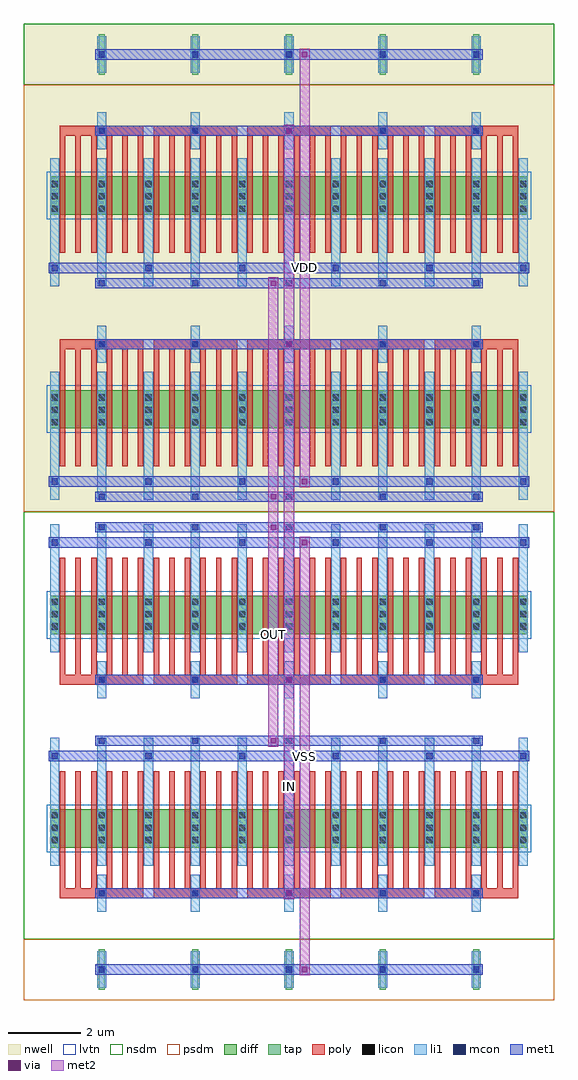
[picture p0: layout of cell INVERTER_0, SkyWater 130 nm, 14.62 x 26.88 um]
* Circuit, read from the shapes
.subckt INVERTER_0 IN OUT VDD VSS
XM1 n1 IN VSS VSS sky130_fd_pr__nfet_01v8_lvt w=1.05 l=0.15
XM2 n2 IN VSS VSS sky130_fd_pr__nfet_01v8_lvt w=1.05 l=0.15
XM3 n3 IN n1 VSS sky130_fd_pr__nfet_01v8_lvt w=1.05 l=0.15
XM4 n4 IN n2 VSS sky130_fd_pr__nfet_01v8_lvt w=1.05 l=0.15
XM5 OUT IN n3 VSS sky130_fd_pr__nfet_01v8_lvt w=1.05 l=0.15
XM6 OUT IN n4 VSS sky130_fd_pr__nfet_01v8_lvt w=1.05 l=0.15
XM7 n5 IN OUT VSS sky130_fd_pr__nfet_01v8_lvt w=1.05 l=0.15
XM8 n6 IN OUT VSS sky130_fd_pr__nfet_01v8_lvt w=1.05 l=0.15
XM9 n7 IN n5 VSS sky130_fd_pr__nfet_01v8_lvt w=1.05 l=0.15
XM10 n8 IN n6 VSS sky130_fd_pr__nfet_01v8_lvt w=1.05 l=0.15
XM11 VSS IN n7 VSS sky130_fd_pr__nfet_01v8_lvt w=1.05 l=0.15
XM12 VSS IN n8 VSS sky130_fd_pr__nfet_01v8_lvt w=1.05 l=0.15
XM13 n9 IN VSS VSS sky130_fd_pr__nfet_01v8_lvt w=1.05 l=0.15
XM14 n10 IN VSS VSS sky130_fd_pr__nfet_01v8_lvt w=1.05 l=0.15
XM15 n11 IN n9 VSS sky130_fd_pr__nfet_01v8_lvt w=1.05 l=0.15
XM16 n12 IN n10 VSS sky130_fd_pr__nfet_01v8_lvt w=1.05 l=0.15
XM17 OUT IN n11 VSS sky130_fd_pr__nfet_01v8_lvt w=1.05 l=0.15
XM18 OUT IN n12 VSS sky130_fd_pr__nfet_01v8_lvt w=1.05 l=0.15
XM19 n13 IN OUT VSS sky130_fd_pr__nfet_01v8_lvt w=1.05 l=0.15
XM20 n14 IN OUT VSS sky130_fd_pr__nfet_01v8_lvt w=1.05 l=0.15
XM21 n15 IN n13 VSS sky130_fd_pr__nfet_01v8_lvt w=1.05 l=0.15
XM22 n16 IN n14 VSS sky130_fd_pr__nfet_01v8_lvt w=1.05 l=0.15
XM23 VSS IN n15 VSS sky130_fd_pr__nfet_01v8_lvt w=1.05 l=0.15
XM24 VSS IN n16 VSS sky130_fd_pr__nfet_01v8_lvt w=1.05 l=0.15
XM25 n17 IN VSS VSS sky130_fd_pr__nfet_01v8_lvt w=1.05 l=0.15
XM26 n18 IN VSS VSS sky130_fd_pr__nfet_01v8_lvt w=1.05 l=0.15
XM27 n19 IN n17 VSS sky130_fd_pr__nfet_01v8_lvt w=1.05 l=0.15
XM28 n20 IN n18 VSS sky130_fd_pr__nfet_01v8_lvt w=1.05 l=0.15
XM29 OUT IN n19 VSS sky130_fd_pr__nfet_01v8_lvt w=1.05 l=0.15
XM30 OUT IN n20 VSS sky130_fd_pr__nfet_01v8_lvt w=1.05 l=0.15
XM31 n21 IN OUT VSS sky130_fd_pr__nfet_01v8_lvt w=1.05 l=0.15
XM32 n22 IN OUT VSS sky130_fd_pr__nfet_01v8_lvt w=1.05 l=0.15
XM33 n23 IN n21 VSS sky130_fd_pr__nfet_01v8_lvt w=1.05 l=0.15
XM34 n24 IN n22 VSS sky130_fd_pr__nfet_01v8_lvt w=1.05 l=0.15
XM35 VSS IN n23 VSS sky130_fd_pr__nfet_01v8_lvt w=1.05 l=0.15
XM36 VSS IN n24 VSS sky130_fd_pr__nfet_01v8_lvt w=1.05 l=0.15
XM37 n25 IN VSS VSS sky130_fd_pr__nfet_01v8_lvt w=1.05 l=0.15
XM38 n26 IN VSS VSS sky130_fd_pr__nfet_01v8_lvt w=1.05 l=0.15
XM39 n27 IN n25 VSS sky130_fd_pr__nfet_01v8_lvt w=1.05 l=0.15
XM40 n28 IN n26 VSS sky130_fd_pr__nfet_01v8_lvt w=1.05 l=0.15
XM41 OUT IN n27 VSS sky130_fd_pr__nfet_01v8_lvt w=1.05 l=0.15
XM42 OUT IN n28 VSS sky130_fd_pr__nfet_01v8_lvt w=1.05 l=0.15
XM43 n29 IN OUT VSS sky130_fd_pr__nfet_01v8_lvt w=1.05 l=0.15
XM44 n30 IN OUT VSS sky130_fd_pr__nfet_01v8_lvt w=1.05 l=0.15
XM45 n31 IN n29 VSS sky130_fd_pr__nfet_01v8_lvt w=1.05 l=0.15
XM46 n32 IN n30 VSS sky130_fd_pr__nfet_01v8_lvt w=1.05 l=0.15
XM47 VSS IN n31 VSS sky130_fd_pr__nfet_01v8_lvt w=1.05 l=0.15
XM48 VSS IN n32 VSS sky130_fd_pr__nfet_01v8_lvt w=1.05 l=0.15
XM49 n33 IN VSS VSS sky130_fd_pr__nfet_01v8_lvt w=1.05 l=0.15
XM50 n34 IN VSS VSS sky130_fd_pr__nfet_01v8_lvt w=1.05 l=0.15
XM51 n35 IN n33 VSS sky130_fd_pr__nfet_01v8_lvt w=1.05 l=0.15
XM52 n36 IN n34 VSS sky130_fd_pr__nfet_01v8_lvt w=1.05 l=0.15
XM53 OUT IN n35 VSS sky130_fd_pr__nfet_01v8_lvt w=1.05 l=0.15
XM54 OUT IN n36 VSS sky130_fd_pr__nfet_01v8_lvt w=1.05 l=0.15
XM55 n37 IN OUT VSS sky130_fd_pr__nfet_01v8_lvt w=1.05 l=0.15
XM56 n38 IN OUT VSS sky130_fd_pr__nfet_01v8_lvt w=1.05 l=0.15
XM57 n39 IN n37 VSS sky130_fd_pr__nfet_01v8_lvt w=1.05 l=0.15
XM58 n40 IN n38 VSS sky130_fd_pr__nfet_01v8_lvt w=1.05 l=0.15
XM59 VSS IN n39 VSS sky130_fd_pr__nfet_01v8_lvt w=1.05 l=0.15
XM60 VSS IN n40 VSS sky130_fd_pr__nfet_01v8_lvt w=1.05 l=0.15
XM61 n41 IN VDD VDD sky130_fd_pr__pfet_01v8_lvt w=1.05 l=0.15
XM62 n42 IN VDD VDD sky130_fd_pr__pfet_01v8_lvt w=1.05 l=0.15
XM63 n43 IN n41 VDD sky130_fd_pr__pfet_01v8_lvt w=1.05 l=0.15
XM64 n44 IN n42 VDD sky130_fd_pr__pfet_01v8_lvt w=1.05 l=0.15
XM65 OUT IN n43 VDD sky130_fd_pr__pfet_01v8_lvt w=1.05 l=0.15
XM66 OUT IN n44 VDD sky130_fd_pr__pfet_01v8_lvt w=1.05 l=0.15
XM67 n45 IN OUT VDD sky130_fd_pr__pfet_01v8_lvt w=1.05 l=0.15
XM68 n46 IN OUT VDD sky130_fd_pr__pfet_01v8_lvt w=1.05 l=0.15
XM69 n47 IN n45 VDD sky130_fd_pr__pfet_01v8_lvt w=1.05 l=0.15
XM70 n48 IN n46 VDD sky130_fd_pr__pfet_01v8_lvt w=1.05 l=0.15
XM71 VDD IN n47 VDD sky130_fd_pr__pfet_01v8_lvt w=1.05 l=0.15
XM72 VDD IN n48 VDD sky130_fd_pr__pfet_01v8_lvt w=1.05 l=0.15
XM73 n49 IN VDD VDD sky130_fd_pr__pfet_01v8_lvt w=1.05 l=0.15
XM74 n50 IN VDD VDD sky130_fd_pr__pfet_01v8_lvt w=1.05 l=0.15
XM75 n51 IN n49 VDD sky130_fd_pr__pfet_01v8_lvt w=1.05 l=0.15
XM76 n52 IN n50 VDD sky130_fd_pr__pfet_01v8_lvt w=1.05 l=0.15
XM77 OUT IN n51 VDD sky130_fd_pr__pfet_01v8_lvt w=1.05 l=0.15
XM78 OUT IN n52 VDD sky130_fd_pr__pfet_01v8_lvt w=1.05 l=0.15
XM79 n53 IN OUT VDD sky130_fd_pr__pfet_01v8_lvt w=1.05 l=0.15
XM80 n54 IN OUT VDD sky130_fd_pr__pfet_01v8_lvt w=1.05 l=0.15
XM81 n55 IN n53 VDD sky130_fd_pr__pfet_01v8_lvt w=1.05 l=0.15
XM82 n56 IN n54 VDD sky130_fd_pr__pfet_01v8_lvt w=1.05 l=0.15
XM83 VDD IN n55 VDD sky130_fd_pr__pfet_01v8_lvt w=1.05 l=0.15
XM84 VDD IN n56 VDD sky130_fd_pr__pfet_01v8_lvt w=1.05 l=0.15
XM85 n57 IN VDD VDD sky130_fd_pr__pfet_01v8_lvt w=1.05 l=0.15
XM86 n58 IN VDD VDD sky130_fd_pr__pfet_01v8_lvt w=1.05 l=0.15
XM87 n59 IN n57 VDD sky130_fd_pr__pfet_01v8_lvt w=1.05 l=0.15
XM88 n60 IN n58 VDD sky130_fd_pr__pfet_01v8_lvt w=1.05 l=0.15
XM89 OUT IN n59 VDD sky130_fd_pr__pfet_01v8_lvt w=1.05 l=0.15
XM90 OUT IN n60 VDD sky130_fd_pr__pfet_01v8_lvt w=1.05 l=0.15
XM91 n61 IN OUT VDD sky130_fd_pr__pfet_01v8_lvt w=1.05 l=0.15
XM92 n62 IN OUT VDD sky130_fd_pr__pfet_01v8_lvt w=1.05 l=0.15
XM93 n63 IN n61 VDD sky130_fd_pr__pfet_01v8_lvt w=1.05 l=0.15
XM94 n64 IN n62 VDD sky130_fd_pr__pfet_01v8_lvt w=1.05 l=0.15
XM95 VDD IN n63 VDD sky130_fd_pr__pfet_01v8_lvt w=1.05 l=0.15
XM96 VDD IN n64 VDD sky130_fd_pr__pfet_01v8_lvt w=1.05 l=0.15
XM97 n65 IN VDD VDD sky130_fd_pr__pfet_01v8_lvt w=1.05 l=0.15
XM98 n66 IN VDD VDD sky130_fd_pr__pfet_01v8_lvt w=1.05 l=0.15
XM99 n67 IN n65 VDD sky130_fd_pr__pfet_01v8_lvt w=1.05 l=0.15
XM100 n68 IN n66 VDD sky130_fd_pr__pfet_01v8_lvt w=1.05 l=0.15
XM101 OUT IN n67 VDD sky130_fd_pr__pfet_01v8_lvt w=1.05 l=0.15
XM102 OUT IN n68 VDD sky130_fd_pr__pfet_01v8_lvt w=1.05 l=0.15
XM103 n69 IN OUT VDD sky130_fd_pr__pfet_01v8_lvt w=1.05 l=0.15
XM104 n70 IN OUT VDD sky130_fd_pr__pfet_01v8_lvt w=1.05 l=0.15
XM105 n71 IN n69 VDD sky130_fd_pr__pfet_01v8_lvt w=1.05 l=0.15
XM106 n72 IN n70 VDD sky130_fd_pr__pfet_01v8_lvt w=1.05 l=0.15
XM107 VDD IN n71 VDD sky130_fd_pr__pfet_01v8_lvt w=1.05 l=0.15
XM108 VDD IN n72 VDD sky130_fd_pr__pfet_01v8_lvt w=1.05 l=0.15
XM109 n73 IN VDD VDD sky130_fd_pr__pfet_01v8_lvt w=1.05 l=0.15
XM110 n74 IN VDD VDD sky130_fd_pr__pfet_01v8_lvt w=1.05 l=0.15
XM111 n75 IN n73 VDD sky130_fd_pr__pfet_01v8_lvt w=1.05 l=0.15
XM112 n76 IN n74 VDD sky130_fd_pr__pfet_01v8_lvt w=1.05 l=0.15
XM113 OUT IN n75 VDD sky130_fd_pr__pfet_01v8_lvt w=1.05 l=0.15
XM114 OUT IN n76 VDD sky130_fd_pr__pfet_01v8_lvt w=1.05 l=0.15
XM115 n77 IN OUT VDD sky130_fd_pr__pfet_01v8_lvt w=1.05 l=0.15
XM116 n78 IN OUT VDD sky130_fd_pr__pfet_01v8_lvt w=1.05 l=0.15
XM117 n79 IN n77 VDD sky130_fd_pr__pfet_01v8_lvt w=1.05 l=0.15
XM118 n80 IN n78 VDD sky130_fd_pr__pfet_01v8_lvt w=1.05 l=0.15
XM119 VDD IN n79 VDD sky130_fd_pr__pfet_01v8_lvt w=1.05 l=0.15
XM120 VDD IN n80 VDD sky130_fd_pr__pfet_01v8_lvt w=1.05 l=0.15
.ends

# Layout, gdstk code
import gdstk
lib = gdstk.Library(unit=1e-6, precision=1e-09)
def R(c, l, rs):  # rectangles x0, y0, x1, y1
    for r in rs: c.add(gdstk.rectangle(r[:2], r[2:], *l))
def A(c, l, x, y, w, h, nx, ny, dx, dy):  # array of equal rectangles
    R(c, l, [(x+i*dx, y+j*dy, x+i*dx+w, y+j*dy+h) for i in range(nx) for j in range(ny)])
def P(c, l, *ps):  # polygons
    for p in ps: c.add(gdstk.Polygon(p, *l))
nwell = (64, 20)
diff = (65, 20)
tap = (65, 44)
poly = (66, 20)
licon = (66, 44)
li1 = (67, 20)
mcon = (67, 44)
met1 = (68, 20)
via = (68, 44)
met2 = (69, 20)
nsdm = (93, 44)
psdm = (94, 20)
lvtn = (125, 44)

nmos_s_10961373_x5_y2_17 = lib.new_cell('NMOS_S_10961373_X5_Y2_1782175707_1782175707')
R(nmos_s_10961373_x5_y2_17, diff, [(0.735,2.31,13.885,3.36), (0.735,8.19,13.885,9.24)])
A(nmos_s_10961373_x5_y2_17, tap, 2.065, 12.04, 0.17, 1.12, 5, 1, 2.58, 0)
A(nmos_s_10961373_x5_y2_17, poly, 1, 1.26, 0.15, 3.36, 30, 2, 0.43, 5.88)
A(nmos_s_10961373_x5_y2_17, poly, 1, 4.485, 2.3, 0.27, 5, 2, 2.58, 5.88)
A(nmos_s_10961373_x5_y2_17, licon, 0.775, 2.39, 0.17, 0.17, 3, 3, 1.29, 0.34)
A(nmos_s_10961373_x5_y2_17, licon, 3.355, 2.39, 0.17, 0.17, 3, 3, 1.29, 0.34)
A(nmos_s_10961373_x5_y2_17, licon, 5.935, 2.39, 0.17, 0.17, 3, 3, 1.29, 0.34)
A(nmos_s_10961373_x5_y2_17, licon, 8.515, 2.39, 0.17, 0.17, 3, 3, 1.29, 0.34)
A(nmos_s_10961373_x5_y2_17, licon, 11.095, 2.39, 0.17, 0.17, 3, 3, 1.29, 0.34)
A(nmos_s_10961373_x5_y2_17, licon, 2.065, 4.535, 0.17, 0.17, 5, 2, 2.58, 5.88)
A(nmos_s_10961373_x5_y2_17, licon, 0.775, 8.27, 0.17, 0.17, 3, 3, 1.29, 0.34)
A(nmos_s_10961373_x5_y2_17, licon, 3.355, 8.27, 0.17, 0.17, 3, 3, 1.29, 0.34)
A(nmos_s_10961373_x5_y2_17, licon, 5.935, 8.27, 0.17, 0.17, 3, 3, 1.29, 0.34)
A(nmos_s_10961373_x5_y2_17, licon, 8.515, 8.27, 0.17, 0.17, 3, 3, 1.29, 0.34)
A(nmos_s_10961373_x5_y2_17, licon, 11.095, 8.27, 0.17, 0.17, 3, 3, 1.29, 0.34)
R(nmos_s_10961373_x5_y2_17, licon, [(2.065,12.515,2.235,12.685), (2.065,12.515,2.235,12.685), (4.645,12.515,4.815,12.685), (4.645,12.515,4.815,12.685), (7.225,12.515,7.395,12.685), (7.225,12.515,7.395,12.685), (9.805,12.515,9.975,12.685), (9.805,12.515,9.975,12.685), (12.385,12.515,12.555,12.685), (12.385,12.515,12.555,12.685)])
A(nmos_s_10961373_x5_y2_17, li1, 0.735, 0.335, 0.25, 3.53, 11, 2, 1.29, 5.88)
A(nmos_s_10961373_x5_y2_17, li1, 2.025, 4.115, 0.25, 1.01, 5, 2, 2.58, 5.88)
A(nmos_s_10961373_x5_y2_17, li1, 2.025, 12.095, 0.25, 1.01, 5, 1, 2.58, 0)
A(nmos_s_10961373_x5_y2_17, mcon, 2.065, 0.335, 0.17, 0.17, 5, 2, 2.58, 4.2)
A(nmos_s_10961373_x5_y2_17, mcon, 0.775, 0.755, 0.17, 0.17, 6, 2, 2.58, 5.88)
A(nmos_s_10961373_x5_y2_17, mcon, 2.065, 6.215, 0.17, 0.17, 5, 2, 2.58, 4.2)
A(nmos_s_10961373_x5_y2_17, mcon, 2.065, 12.515, 0.17, 0.17, 5, 1, 2.58, 0)
R(nmos_s_10961373_x5_y2_17, met1, [(1.98,0.28,12.64,0.56), (0.69,0.7,13.93,0.98), (1.98,4.48,12.64,4.76), (1.98,6.16,12.64,6.44), (0.69,6.58,13.93,6.86), (1.98,10.36,12.64,10.64), (1.98,12.46,12.64,12.74)])
A(nmos_s_10961373_x5_y2_17, via, 7.665, 0.765, 0.15, 0.15, 1, 3, 0, 5.88)
R(nmos_s_10961373_x5_y2_17, via, [(6.805,0.345,6.955,0.495), (7.235,4.545,7.385,4.695), (6.805,6.225,6.955,6.375), (7.235,10.425,7.385,10.575)])
R(nmos_s_10961373_x5_y2_17, met2, [(6.74,0.26,7.02,6.46), (7.6,0.68,7.88,12.76), (7.17,4.46,7.45,10.66)])
R(nmos_s_10961373_x5_y2_17, nsdm, [(0,0,14.62,11.76)])
R(nmos_s_10961373_x5_y2_17, psdm, [(0,11.76,14.62,13.44)])
R(nmos_s_10961373_x5_y2_17, lvtn, [(0.645,2.18,13.975,3.49), (0.645,8.06,13.975,9.37)])

pmos_s_70655723_x5_y2_17 = lib.new_cell('PMOS_S_70655723_X5_Y2_1782175708_1782175707')
R(pmos_s_70655723_x5_y2_17, nwell, [(0,0,14.62,13.44)])
R(pmos_s_70655723_x5_y2_17, diff, [(0.735,2.31,13.885,3.36), (0.735,8.19,13.885,9.24)])
A(pmos_s_70655723_x5_y2_17, tap, 2.065, 12.04, 0.17, 1.12, 5, 1, 2.58, 0)
A(pmos_s_70655723_x5_y2_17, poly, 1, 1.26, 0.15, 3.36, 30, 2, 0.43, 5.88)
A(pmos_s_70655723_x5_y2_17, poly, 1, 4.485, 2.3, 0.27, 5, 2, 2.58, 5.88)
A(pmos_s_70655723_x5_y2_17, licon, 0.775, 2.39, 0.17, 0.17, 3, 3, 1.29, 0.34)
A(pmos_s_70655723_x5_y2_17, licon, 3.355, 2.39, 0.17, 0.17, 3, 3, 1.29, 0.34)
A(pmos_s_70655723_x5_y2_17, licon, 5.935, 2.39, 0.17, 0.17, 3, 3, 1.29, 0.34)
A(pmos_s_70655723_x5_y2_17, licon, 8.515, 2.39, 0.17, 0.17, 3, 3, 1.29, 0.34)
A(pmos_s_70655723_x5_y2_17, licon, 11.095, 2.39, 0.17, 0.17, 3, 3, 1.29, 0.34)
A(pmos_s_70655723_x5_y2_17, licon, 2.065, 4.535, 0.17, 0.17, 5, 2, 2.58, 5.88)
A(pmos_s_70655723_x5_y2_17, licon, 0.775, 8.27, 0.17, 0.17, 3, 3, 1.29, 0.34)
A(pmos_s_70655723_x5_y2_17, licon, 3.355, 8.27, 0.17, 0.17, 3, 3, 1.29, 0.34)
A(pmos_s_70655723_x5_y2_17, licon, 5.935, 8.27, 0.17, 0.17, 3, 3, 1.29, 0.34)
A(pmos_s_70655723_x5_y2_17, licon, 8.515, 8.27, 0.17, 0.17, 3, 3, 1.29, 0.34)
A(pmos_s_70655723_x5_y2_17, licon, 11.095, 8.27, 0.17, 0.17, 3, 3, 1.29, 0.34)
R(pmos_s_70655723_x5_y2_17, licon, [(2.065,12.515,2.235,12.685), (2.065,12.515,2.235,12.685), (4.645,12.515,4.815,12.685), (4.645,12.515,4.815,12.685), (7.225,12.515,7.395,12.685), (7.225,12.515,7.395,12.685), (9.805,12.515,9.975,12.685), (9.805,12.515,9.975,12.685), (12.385,12.515,12.555,12.685), (12.385,12.515,12.555,12.685)])
A(pmos_s_70655723_x5_y2_17, li1, 0.735, 0.335, 0.25, 3.53, 11, 2, 1.29, 5.88)
A(pmos_s_70655723_x5_y2_17, li1, 2.025, 4.115, 0.25, 1.01, 5, 2, 2.58, 5.88)
A(pmos_s_70655723_x5_y2_17, li1, 2.025, 12.095, 0.25, 1.01, 5, 1, 2.58, 0)
A(pmos_s_70655723_x5_y2_17, mcon, 2.065, 0.335, 0.17, 0.17, 5, 2, 2.58, 4.2)
A(pmos_s_70655723_x5_y2_17, mcon, 0.775, 0.755, 0.17, 0.17, 6, 2, 2.58, 5.88)
A(pmos_s_70655723_x5_y2_17, mcon, 2.065, 6.215, 0.17, 0.17, 5, 2, 2.58, 4.2)
A(pmos_s_70655723_x5_y2_17, mcon, 2.065, 12.515, 0.17, 0.17, 5, 1, 2.58, 0)
R(pmos_s_70655723_x5_y2_17, met1, [(1.98,0.28,12.64,0.56), (0.69,0.7,13.93,0.98), (1.98,4.48,12.64,4.76), (1.98,6.16,12.64,6.44), (0.69,6.58,13.93,6.86), (1.98,10.36,12.64,10.64), (1.98,12.46,12.64,12.74)])
A(pmos_s_70655723_x5_y2_17, via, 7.665, 0.765, 0.15, 0.15, 1, 3, 0, 5.88)
R(pmos_s_70655723_x5_y2_17, via, [(6.805,0.345,6.955,0.495), (7.235,4.545,7.385,4.695), (6.805,6.225,6.955,6.375), (7.235,10.425,7.385,10.575)])
R(pmos_s_70655723_x5_y2_17, met2, [(6.74,0.26,7.02,6.46), (7.6,0.68,7.88,12.76), (7.17,4.46,7.45,10.66)])
R(pmos_s_70655723_x5_y2_17, nsdm, [(0,11.76,14.62,13.44)])
R(pmos_s_70655723_x5_y2_17, psdm, [(0,0,14.62,11.76)])
R(pmos_s_70655723_x5_y2_17, lvtn, [(0.645,2.18,13.975,3.49), (0.645,8.06,13.975,9.37)])

inv_3799024_0_0_17821757 = lib.new_cell('INV_3799024_0_0_1782175707')
R(inv_3799024_0_0_17821757, met2, [(7.17,8.82,7.45,18.06), (6.74,13.02,7.02,13.86)])
P(inv_3799024_0_0_17821757, met2, [(0,0),(0,0),(0,0),(0,0)],
  [(0,0),(0,0),(0,0),(0,0)],
  [(0,0),(0,0),(0,0),(0,0)],
  [(0,0),(0,0),(0,0),(0,0)],
  [(0,0),(0,0),(0,0),(0,0)],
  [(0,0),(0,0),(0,0),(0,0)])
inv_3799024_0_0_17821757.add(gdstk.Reference(nmos_s_10961373_x5_y2_17, (0,13.44), x_reflection=True))
inv_3799024_0_0_17821757.add(gdstk.Reference(pmos_s_70655723_x5_y2_17, (0,13.44)))

inverter_0 = lib.new_cell('INVERTER_0')
P(inverter_0, met2, [(0,0),(0,0),(0,0),(0,0)],
  [(0,0),(0,0),(0,0),(0,0)],
  [(0,0),(0,0),(0,0),(0,0)],
  [(0,0),(0,0),(0,0),(0,0)],
  [(0,0),(0,0),(0,0),(0,0)],
  [(0,0),(0,0),(0,0),(0,0)],
  [(0,0),(0,0),(0,0),(0,0)],
  [(0,0),(0,0),(0,0),(0,0)],
  [(0,0),(0,0),(0,0),(0,0)],
  [(0,0),(0,0),(0,0),(0,0)],
  [(0,0),(0,0),(0,0),(0,0)],
  [(0,0),(0,0),(0,0),(0,0)])
inverter_0.add(gdstk.Reference(inv_3799024_0_0_17821757, (0,0)))
inverter_0.add(gdstk.Label('IN', (7.31,5.88), layer=69, texttype=5))
inverter_0.add(gdstk.Label('VSS', (7.74,6.72), layer=69, texttype=5))
inverter_0.add(gdstk.Label('VDD', (7.74,20.16), layer=69, texttype=5))
inverter_0.add(gdstk.Label('OUT', (6.88,10.08), layer=69, texttype=5))

lib.write_gds('INVERTER_0.gds')
